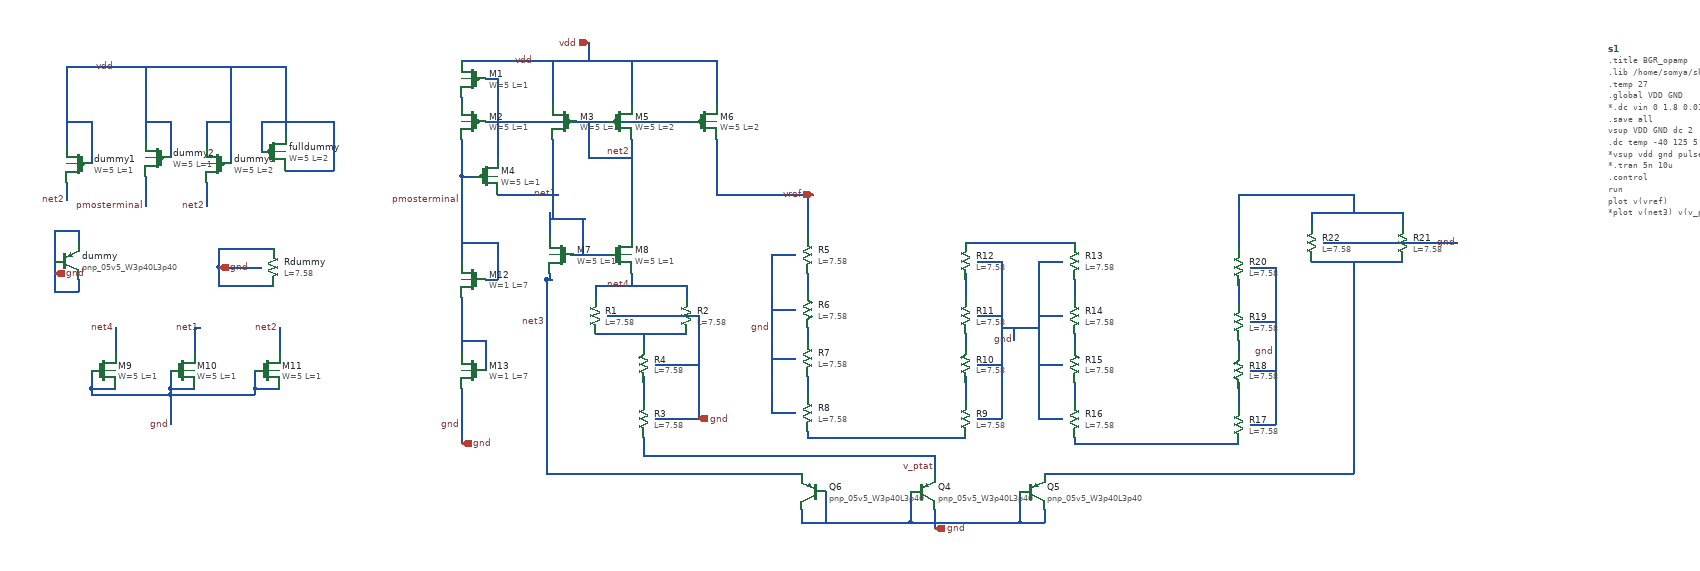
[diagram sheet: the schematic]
v {xschem version=3.4.8RC file_version=1.2}
G {}
K {}
V {}
S {}
E {}
N -70 -320 -70 -310 {lab=#net5}
N -70 -380 90 -380 {lab=vdd}
N 80 -380 80 -310 {lab=vdd}
N -10 -230 -10 -220 {lab=net2}
N 210 -380 210 -310 {lab=vdd}
N 80 -380 210 -380 {lab=vdd}
N 350 -380 350 -310 {lab=vdd}
N 200 -380 350 -380 {lab=vdd}
N -30 -280 150 -280 {lab=net2}
N 130 -280 310 -280 {lab=net2}
N -10 -160 90 -160 {lab=net1}
N -10 -280 -10 -230 {lab=net2}
N -70 -250 -70 -190 {lab=pmosterminal}
N -70 -190 -50 -190 {lab=pmosterminal}
N 140 -410 140 -380 {lab=vdd}
N -30 -350 -10 -350 {lab=net2}
N -10 -350 -10 -280 {lab=net2}
N 80 -250 80 -160 {lab=net1}
N 350 -250 350 -190 {lab=vref}
N 210 -250 210 -200 {lab=net2}
N 140 -280 140 -220 {lab=net2}
N 140 -220 210 -220 {lab=net2}
N -70 -190 -70 -120 {lab=pmosterminal}
N -720 -370 -720 -240 {lab=vdd}
N -720 -370 -560 -370 {lab=vdd}
N -490 -180 -490 -140 {lab=net2}
N -400 -280 -400 -230 {lab=vdd}
N -400 -280 -360 -280 {lab=vdd}
N -360 -200 -280 -200 {lab=vdd}
N -280 -280 -280 -200 {lab=vdd}
N -360 -280 -280 -280 {lab=vdd}
N 75 -120 135 -120 {lab=net1}
N 75 -130 75 -90 {lab=net1}
N 75 -30 75 -20 {lab=net3}
N 110 -60 170 -60 {lab=net1}
N 130 -120 130 -60 {lab=net1}
N -680 130 -680 160 {lab=gnd}
N -680 160 -640 160 {lab=gnd}
N -680 160 -680 170 {lab=gnd}
N -640 60 -640 100 {lab=net4}
N -550 130 -550 160 {lab=gnd}
N -550 160 -510 160 {lab=gnd}
N -680 170 -550 170 {lab=gnd}
N -550 160 -550 170 {lab=gnd}
N -510 60 -510 100 {lab=net1}
N -510 60 -500 60 {lab=net1}
N -370 60 -370 100 {lab=net2}
N -410 130 -410 160 {lab=gnd}
N -410 160 -370 160 {lab=gnd}
N -670 170 -410 170 {lab=gnd}
N -410 160 -410 170 {lab=gnd}
N -550 170 -550 220 {lab=gnd}
N -30 -20 -10 -20 {lab=pmosterminal}
N -70 160 -70 180 {lab=gnd}
N -70 10 -70 100 {lab=#net6}
N -70 -120 -70 -50 {lab=pmosterminal}
N -10 -80 -10 -20 {lab=pmosterminal}
N -70 -80 -10 -80 {lab=pmosterminal}
N -70 180 -70 210 {lab=gnd}
N -30 80 -30 130 {lab=#net6}
N -70 80 -30 80 {lab=#net6}
N -70 210 -70 250 {lab=gnd}
N 150 70 300 70 {lab=#net7}
N 300 -10 300 10 {lab=net4}
N 150 -10 300 -10 {lab=net4}
N 150 -10 150 10 {lab=net4}
N 230 140 230 180 {lab=#net8}
N 230 70 230 90 {lab=#net7}
N 230 240 230 270 {lab=v_ptat}
N 170 40 320 40 {lab=gnd}
N 320 40 320 210 {lab=gnd}
N 250 210 320 210 {lab=gnd}
N 250 120 320 120 {lab=gnd}
N 500 -30 500 10 {lab=#net9}
N 500 60 500 80 {lab=#net10}
N 500 140 500 180 {lab=#net11}
N 440 -60 480 -60 {lab=gnd}
N 440 -60 440 200 {lab=gnd}
N 440 200 480 200 {lab=gnd}
N 440 110 480 110 {lab=gnd}
N 440 30 480 30 {lab=gnd}
N 760 140 760 180 {lab=#net12}
N 760 70 760 90 {lab=#net13}
N 760 -30 760 10 {lab=#net14}
N 780 210 820 210 {lab=gnd}
N 820 -50 820 210 {lab=gnd}
N 780 -50 820 -50 {lab=gnd}
N 780 40 820 40 {lab=gnd}
N 780 120 820 120 {lab=gnd}
N 940 -20 940 20 {lab=#net15}
N 940 70 940 90 {lab=#net16}
N 940 150 940 190 {lab=#net17}
N 880 -50 920 -50 {lab=gnd}
N 880 -50 880 210 {lab=gnd}
N 880 210 920 210 {lab=gnd}
N 880 120 920 120 {lab=gnd}
N 880 40 920 40 {lab=gnd}
N 1210 150 1210 190 {lab=#net18}
N 1210 80 1210 100 {lab=#net19}
N 1210 -20 1210 20 {lab=#net20}
N 1230 220 1270 220 {lab=gnd}
N 1270 -40 1270 220 {lab=gnd}
N 1230 -40 1270 -40 {lab=gnd}
N 1230 50 1270 50 {lab=gnd}
N 1230 130 1270 130 {lab=gnd}
N 820 60 880 60 {lab=gnd}
N 840 60 840 80 {lab=gnd}
N 500 230 500 240 {lab=#net21}
N 500 240 760 240 {lab=#net21}
N 760 -80 940 -80 {lab=#net22}
N 940 240 940 250 {lab=#net23}
N 940 250 1210 250 {lab=#net23}
N 1480 -130 1480 -110 {lab=#net24}
N 1330 -130 1480 -130 {lab=#net24}
N 1330 -130 1330 -110 {lab=#net24}
N 1350 -80 1500 -80 {lab=gnd}
N 1330 -50 1480 -50 {lab=#net25}
N 1400 -50 1400 0 {lab=#net25}
N 1500 -80 1570 -80 {lab=gnd}
N 1210 -160 1210 -70 {lab=#net24}
N 1210 -160 1400 -160 {lab=#net24}
N 1400 -160 1400 -130 {lab=#net24}
N -470 -70 -470 -40 {lab=gnd}
N -470 -70 -380 -70 {lab=gnd}
N -470 -40 -470 -10 {lab=gnd}
N -470 -10 -380 -10 {lab=gnd}
N -470 -40 -400 -40 {lab=gnd}
N 350 -190 350 -160 {lab=vref}
N 350 -160 510 -160 {lab=vref}
N 710 360 710 390 {lab=gnd}
N 670 330 670 380 {lab=gnd}
N 670 380 710 380 {lab=gnd}
N 490 360 490 380 {lab=gnd}
N 490 380 670 380 {lab=gnd}
N 530 330 530 380 {lab=gnd}
N 850 330 850 380 {lab=gnd}
N 710 380 850 380 {lab=gnd}
N 890 360 890 380 {lab=gnd}
N 850 380 890 380 {lab=gnd}
N -700 -20 -700 0 {lab=gnd}
N -740 -50 -740 0 {lab=gnd}
N -740 0 -700 0 {lab=gnd}
N -700 -100 -700 -80 {lab=gnd}
N -740 -100 -700 -100 {lab=gnd}
N -740 -100 -740 -50 {lab=gnd}
N 500 -160 500 -90 {lab=vref}
N 230 270 710 270 {lab=v_ptat}
N 70 -20 70 0 {lab=net3}
N 70 -20 80 -20 {lab=net3}
N -680 -280 -680 -210 {lab=vdd}
N -720 -280 -680 -280 {lab=vdd}
N -590 -370 -590 -250 {lab=vdd}
N -450 -370 -450 -210 {lab=vdd}
N -490 -280 -490 -240 {lab=vdd}
N -490 -280 -450 -280 {lab=vdd}
N -550 -280 -550 -220 {lab=vdd}
N -590 -280 -550 -280 {lab=vdd}
N -720 -180 -720 -150 {lab=net2}
N -590 -190 -590 -140 {lab=pmosterminal}
N -360 -370 -360 -260 {lab=vdd}
N -590 -370 -360 -370 {lab=vdd}
N 210 -220 210 -90 {lab=net2}
N 80 -160 80 -120 {lab=net1}
N 210 -30 210 -10 {lab=net4}
N 710 270 710 300 {lab=v_ptat}
N 70 -20 70 300 {lab=net3}
N 70 300 490 300 {lab=net3}
N 1400 -40 1400 300 {lab=#net25}
N 890 300 1400 300 {lab=#net25}
C {sky130_fd_pr/pfet3_01v8.sym} -50 -350 0 1 {name=M1
W=5
L=1
body=VDD
nf=1
mult=1
ad="expr('int((@nf + 1)/2) * @W / @nf * 0.29')"
pd="expr('2*int((@nf + 1)/2) * (@W / @nf + 0.29)')"
as="expr('int((@nf + 2)/2) * @W / @nf * 0.29')"
ps="expr('2*int((@nf + 2)/2) * (@W / @nf + 0.29)')"
nrd="expr('0.29 / @W ')" nrs="expr('0.29 / @W ')"
sa=0 sb=0 sd=0
model=pfet_01v8
spiceprefix=X
}
C {sky130_fd_pr/pfet3_01v8.sym} -50 -280 0 1 {name=M2
W=5
L=1
body=VDD
nf=1
mult=1
ad="expr('int((@nf + 1)/2) * @W / @nf * 0.29')"
pd="expr('2*int((@nf + 1)/2) * (@W / @nf + 0.29)')"
as="expr('int((@nf + 2)/2) * @W / @nf * 0.29')"
ps="expr('2*int((@nf + 2)/2) * (@W / @nf + 0.29)')"
nrd="expr('0.29 / @W ')" nrs="expr('0.29 / @W ')"
sa=0 sb=0 sd=0
model=pfet_01v8
spiceprefix=X
}
C {sky130_fd_pr/pfet3_01v8.sym} 100 -280 0 1 {name=M3
W=5
L=2
body=VDD
nf=1
mult=4
ad="expr('int((@nf + 1)/2) * @W / @nf * 0.29')"
pd="expr('2*int((@nf + 1)/2) * (@W / @nf + 0.29)')"
as="expr('int((@nf + 2)/2) * @W / @nf * 0.29')"
ps="expr('2*int((@nf + 2)/2) * (@W / @nf + 0.29)')"
nrd="expr('0.29 / @W ')" nrs="expr('0.29 / @W ')"
sa=0 sb=0 sd=0
model=pfet_01v8
spiceprefix=X
}
C {sky130_fd_pr/pfet3_01v8.sym} -30 -190 0 0 {name=M4
W=5
L=1
body=VDD
nf=1
mult=2
ad="expr('int((@nf + 1)/2) * @W / @nf * 0.29')"
pd="expr('2*int((@nf + 1)/2) * (@W / @nf + 0.29)')"
as="expr('int((@nf + 2)/2) * @W / @nf * 0.29')"
ps="expr('2*int((@nf + 2)/2) * (@W / @nf + 0.29)')"
nrd="expr('0.29 / @W ')" nrs="expr('0.29 / @W ')"
sa=0 sb=0 sd=0
model=pfet_01v8
spiceprefix=X
}
C {sky130_fd_pr/pfet3_01v8.sym} 190 -280 0 0 {name=M5
W=5
L=2
body=VDD
nf=1
mult=4
ad="expr('int((@nf + 1)/2) * @W / @nf * 0.29')"
pd="expr('2*int((@nf + 1)/2) * (@W / @nf + 0.29)')"
as="expr('int((@nf + 2)/2) * @W / @nf * 0.29')"
ps="expr('2*int((@nf + 2)/2) * (@W / @nf + 0.29)')"
nrd="expr('0.29 / @W ')" nrs="expr('0.29 / @W ')"
sa=0 sb=0 sd=0
model=pfet_01v8
spiceprefix=X
}
C {sky130_fd_pr/pfet3_01v8.sym} 330 -280 0 0 {name=M6
W=5
L=2
body=VDD
nf=1
mult=4
ad="expr('int((@nf + 1)/2) * @W / @nf * 0.29')"
pd="expr('2*int((@nf + 1)/2) * (@W / @nf + 0.29)')"
as="expr('int((@nf + 2)/2) * @W / @nf * 0.29')"
ps="expr('2*int((@nf + 2)/2) * (@W / @nf + 0.29)')"
nrd="expr('0.29 / @W ')" nrs="expr('0.29 / @W ')"
sa=0 sb=0 sd=0
model=pfet_01v8
spiceprefix=X
}
C {iopin.sym} 140 -410 0 0 {name=p1 lab=vdd}
C {iopin.sym} 510 -160 0 0 {name=p5 lab=vref}
C {sky130_fd_pr/pfet3_01v8.sym} -570 -220 0 1 {name=dummy2
W=5
L=1
body=VDD
nf=1
mult=1
ad="expr('int((@nf + 1)/2) * @W / @nf * 0.29')"
pd="expr('2*int((@nf + 1)/2) * (@W / @nf + 0.29)')"
as="expr('int((@nf + 2)/2) * @W / @nf * 0.29')"
ps="expr('2*int((@nf + 2)/2) * (@W / @nf + 0.29)')"
nrd="expr('0.29 / @W ')" nrs="expr('0.29 / @W ')"
sa=0 sb=0 sd=0
model=pfet_01v8
spiceprefix=X
}
C {sky130_fd_pr/pfet3_01v8.sym} -700 -210 0 1 {name=dummy1
W=5
L=1
body=VDD
nf=1
mult=1
ad="expr('int((@nf + 1)/2) * @W / @nf * 0.29')"
pd="expr('2*int((@nf + 1)/2) * (@W / @nf + 0.29)')"
as="expr('int((@nf + 2)/2) * @W / @nf * 0.29')"
ps="expr('2*int((@nf + 2)/2) * (@W / @nf + 0.29)')"
nrd="expr('0.29 / @W ')" nrs="expr('0.29 / @W ')"
sa=0 sb=0 sd=0
model=pfet_01v8
spiceprefix=X
}
C {sky130_fd_pr/pfet3_01v8.sym} -470 -210 0 1 {name=dummy3
W=5
L=2
body=VDD
nf=1
mult=1
ad="expr('int((@nf + 1)/2) * @W / @nf * 0.29')"
pd="expr('2*int((@nf + 1)/2) * (@W / @nf + 0.29)')"
as="expr('int((@nf + 2)/2) * @W / @nf * 0.29')"
ps="expr('2*int((@nf + 2)/2) * (@W / @nf + 0.29)')"
nrd="expr('0.29 / @W ')" nrs="expr('0.29 / @W ')"
sa=0 sb=0 sd=0
model=pfet_01v8
spiceprefix=X
}
C {sky130_fd_pr/pfet3_01v8.sym} -380 -230 0 0 {name=fulldummy
W=5
L=2
body=VDD
nf=1
mult=4
ad="expr('int((@nf + 1)/2) * @W / @nf * 0.29')"
pd="expr('2*int((@nf + 1)/2) * (@W / @nf + 0.29)')"
as="expr('int((@nf + 2)/2) * @W / @nf * 0.29')"
ps="expr('2*int((@nf + 2)/2) * (@W / @nf + 0.29)')"
nrd="expr('0.29 / @W ')" nrs="expr('0.29 / @W ')"
sa=0 sb=0 sd=0
model=pfet_01v8
spiceprefix=X
}
C {sky130_fd_pr/nfet3_01v8.sym} 95 -60 0 1 {name=M7
W=5
L=1
body=GND
nf=1
mult=8
ad="expr('int((@nf + 1)/2) * @W / @nf * 0.29')"
pd="expr('2*int((@nf + 1)/2) * (@W / @nf + 0.29)')"
as="expr('int((@nf + 2)/2) * @W / @nf * 0.29')"
ps="expr('2*int((@nf + 2)/2) * (@W / @nf + 0.29)')"
nrd="expr('0.29 / @W ')" nrs="expr('0.29 / @W ')"
sa=0 sb=0 sd=0
model=nfet_01v8
spiceprefix=X
}
C {sky130_fd_pr/nfet3_01v8.sym} 190 -60 0 0 {name=M8
W=5
L=1
body=GND
nf=1
mult=8
ad="expr('int((@nf + 1)/2) * @W / @nf * 0.29')"
pd="expr('2*int((@nf + 1)/2) * (@W / @nf + 0.29)')"
as="expr('int((@nf + 2)/2) * @W / @nf * 0.29')"
ps="expr('2*int((@nf + 2)/2) * (@W / @nf + 0.29)')"
nrd="expr('0.29 / @W ')" nrs="expr('0.29 / @W ')"
sa=0 sb=0 sd=0
model=nfet_01v8
spiceprefix=X
}
C {sky130_fd_pr/nfet3_01v8.sym} -660 130 0 0 {name=M9
W=5
L=1
body=GND
nf=1
mult=4
ad="expr('int((@nf + 1)/2) * @W / @nf * 0.29')"
pd="expr('2*int((@nf + 1)/2) * (@W / @nf + 0.29)')"
as="expr('int((@nf + 2)/2) * @W / @nf * 0.29')"
ps="expr('2*int((@nf + 2)/2) * (@W / @nf + 0.29)')"
nrd="expr('0.29 / @W ')" nrs="expr('0.29 / @W ')"
sa=0 sb=0 sd=0
model=nfet_01v8
spiceprefix=X
}
C {sky130_fd_pr/nfet3_01v8.sym} -530 130 0 0 {name=M10
W=5
L=1
body=GND
nf=1
mult=6
ad="expr('int((@nf + 1)/2) * @W / @nf * 0.29')"
pd="expr('2*int((@nf + 1)/2) * (@W / @nf + 0.29)')"
as="expr('int((@nf + 2)/2) * @W / @nf * 0.29')"
ps="expr('2*int((@nf + 2)/2) * (@W / @nf + 0.29)')"
nrd="expr('0.29 / @W ')" nrs="expr('0.29 / @W ')"
sa=0 sb=0 sd=0
model=nfet_01v8
spiceprefix=X
}
C {sky130_fd_pr/nfet3_01v8.sym} -390 130 0 0 {name=M11
W=5
L=1
body=GND
nf=1
mult=2
ad="expr('int((@nf + 1)/2) * @W / @nf * 0.29')"
pd="expr('2*int((@nf + 1)/2) * (@W / @nf + 0.29)')"
as="expr('int((@nf + 2)/2) * @W / @nf * 0.29')"
ps="expr('2*int((@nf + 2)/2) * (@W / @nf + 0.29)')"
nrd="expr('0.29 / @W ')" nrs="expr('0.29 / @W ')"
sa=0 sb=0 sd=0
model=nfet_01v8
spiceprefix=X
}
C {sky130_fd_pr/nfet3_01v8.sym} -50 -20 0 1 {name=M12
W=1
L=7
body=GND
nf=1
mult=1
ad="expr('int((@nf + 1)/2) * @W / @nf * 0.29')"
pd="expr('2*int((@nf + 1)/2) * (@W / @nf + 0.29)')"
as="expr('int((@nf + 2)/2) * @W / @nf * 0.29')"
ps="expr('2*int((@nf + 2)/2) * (@W / @nf + 0.29)')"
nrd="expr('0.29 / @W ')" nrs="expr('0.29 / @W ')"
sa=0 sb=0 sd=0
model=nfet_01v8
spiceprefix=X
}
C {sky130_fd_pr/nfet3_01v8.sym} -50 130 0 1 {name=M13
W=1
L=7
body=GND
nf=1
mult=1
ad="expr('int((@nf + 1)/2) * @W / @nf * 0.29')"
pd="expr('2*int((@nf + 1)/2) * (@W / @nf + 0.29)')"
as="expr('int((@nf + 2)/2) * @W / @nf * 0.29')"
ps="expr('2*int((@nf + 2)/2) * (@W / @nf + 0.29)')"
nrd="expr('0.29 / @W ')" nrs="expr('0.29 / @W ')"
sa=0 sb=0 sd=0
model=nfet_01v8
spiceprefix=X
}
C {sky130_fd_pr/res_high_po_1p41.sym} 300 40 2 0 {name=R2
L=7.58
model=res_high_po_1p41
spiceprefix=X
mult=1}
C {sky130_fd_pr/res_high_po_1p41.sym} 150 40 2 0 {name=R1
L=7.58
model=res_high_po_1p41
spiceprefix=X
mult=1}
C {sky130_fd_pr/res_high_po_1p41.sym} 230 210 2 0 {name=R3
L=7.58
model=res_high_po_1p41
spiceprefix=X
mult=1}
C {sky130_fd_pr/res_high_po_1p41.sym} 230 120 2 0 {name=R4
L=7.58
model=res_high_po_1p41
spiceprefix=X
mult=1}
C {iopin.sym} 320 210 2 1 {name=p18 lab=gnd
}
C {sky130_fd_pr/res_high_po_1p41.sym} 500 -60 0 0 {name=R5
L=7.58
model=res_high_po_1p41
spiceprefix=X
mult=1}
C {sky130_fd_pr/res_high_po_1p41.sym} 500 30 0 0 {name=R6
L=7.58
model=res_high_po_1p41
spiceprefix=X
mult=1}
C {sky130_fd_pr/res_high_po_1p41.sym} 500 110 0 0 {name=R7
L=7.58
model=res_high_po_1p41
spiceprefix=X
mult=1}
C {sky130_fd_pr/res_high_po_1p41.sym} 500 200 0 0 {name=R8
L=7.58
model=res_high_po_1p41
spiceprefix=X
mult=1}
C {sky130_fd_pr/res_high_po_1p41.sym} 760 210 2 0 {name=R9
L=7.58
model=res_high_po_1p41
spiceprefix=X
mult=1}
C {sky130_fd_pr/res_high_po_1p41.sym} 760 120 2 0 {name=R10
L=7.58
model=res_high_po_1p41
spiceprefix=X
mult=1}
C {sky130_fd_pr/res_high_po_1p41.sym} 760 40 2 0 {name=R11
L=7.58
model=res_high_po_1p41
spiceprefix=X
mult=1}
C {sky130_fd_pr/res_high_po_1p41.sym} 760 -50 2 0 {name=R12
L=7.58
model=res_high_po_1p41
spiceprefix=X
mult=1}
C {sky130_fd_pr/res_high_po_1p41.sym} 940 -50 0 0 {name=R13
L=7.58
model=res_high_po_1p41
spiceprefix=X
mult=1}
C {sky130_fd_pr/res_high_po_1p41.sym} 940 40 0 0 {name=R14
L=7.58
model=res_high_po_1p41
spiceprefix=X
mult=1}
C {sky130_fd_pr/res_high_po_1p41.sym} 940 120 0 0 {name=R15
L=7.58
model=res_high_po_1p41
spiceprefix=X
mult=1}
C {sky130_fd_pr/res_high_po_1p41.sym} 940 210 0 0 {name=R16
L=7.58
model=res_high_po_1p41
spiceprefix=X
mult=1}
C {sky130_fd_pr/res_high_po_1p41.sym} 1210 220 2 0 {name=R17
L=7.58
model=res_high_po_1p41
spiceprefix=X
mult=1}
C {sky130_fd_pr/res_high_po_1p41.sym} 1210 130 2 0 {name=R18
L=7.58
model=res_high_po_1p41
spiceprefix=X
mult=1}
C {sky130_fd_pr/res_high_po_1p41.sym} 1210 50 2 0 {name=R19
L=7.58
model=res_high_po_1p41
spiceprefix=X
mult=1}
C {sky130_fd_pr/res_high_po_1p41.sym} 1210 -40 2 0 {name=R20
L=7.58
model=res_high_po_1p41
spiceprefix=X
mult=1}
C {sky130_fd_pr/res_high_po_1p41.sym} 1480 -80 2 0 {name=R21
L=7.58
model=res_high_po_1p41
spiceprefix=X
mult=1}
C {sky130_fd_pr/res_high_po_1p41.sym} 1330 -80 2 0 {name=R22
L=7.58
model=res_high_po_1p41
spiceprefix=X
mult=1}
C {sky130_fd_pr/res_high_po_1p41.sym} -380 -40 0 0 {name=Rdummy
L=7.58
model=res_high_po_1p41
spiceprefix=X
mult=4}
C {iopin.sym} -470 -40 0 1 {name=p25 lab=gnd
}
C {iopin.sym} -70 250 0 1 {name=p2 lab=gnd
}
C {sky130_fd_pr/pnp_05v5.sym} 690 330 0 0 {name=Q4
model=pnp_05v5_W3p40L3p40
m=8
spiceprefix=X
}
C {sky130_fd_pr/pnp_05v5.sym} 870 330 0 0 {name=Q5
model=pnp_05v5_W3p40L3p40
m=1
spiceprefix=X
}
C {sky130_fd_pr/pnp_05v5.sym} 510 330 0 1 {name=Q6
model=pnp_05v5_W3p40L3p40
m=1
spiceprefix=X
}
C {sky130_fd_pr/pnp_05v5.sym} -720 -50 0 0 {name=dummy
model=pnp_05v5_W3p40L3p40
m=18
spiceprefix=X
}
C {iopin.sym} 710 390 0 1 {name=p10 lab=gnd
}
C {iopin.sym} -740 -30 0 1 {name=p22 lab=gnd
}
C {lab_wire.sym} -500 60 0 0 {name=p8 sig_type=std_logic lab=net1}
C {lab_wire.sym} 90 -160 0 0 {name=p12 sig_type=std_logic lab=net1}
C {lab_wire.sym} -370 60 0 0 {name=p14 sig_type=std_logic lab=net2}
C {lab_wire.sym} -640 60 0 0 {name=p3 sig_type=std_logic lab=net4}
C {lab_wire.sym} 210 -10 0 0 {name=p11 sig_type=std_logic lab=net4}
C {lab_wire.sym} 70 50 0 0 {name=p9 sig_type=std_logic lab=net3}
C {lab_wire.sym} 210 -230 0 0 {name=p4 sig_type=std_logic lab=net2}
C {lab_wire.sym} -490 -140 0 0 {name=p7 sig_type=std_logic lab=net2}
C {lab_wire.sym} -720 -150 0 0 {name=p6 sig_type=std_logic lab=net2}
C {lab_wire.sym} -70 220 0 0 {name=p13 sig_type=std_logic lab=gnd}
C {lab_wire.sym} -550 220 0 0 {name=p15 sig_type=std_logic lab=gnd}
C {lab_wire.sym} -70 -150 0 0 {name=p16 sig_type=std_logic lab=pmosterminal}
C {lab_wire.sym} -590 -140 0 0 {name=p17 sig_type=std_logic lab=pmosterminal}
C {lab_wire.sym} 50 -380 0 0 {name=p23 sig_type=std_logic lab=vdd}
C {lab_wire.sym} -640 -370 0 0 {name=p26 sig_type=std_logic lab=vdd}
C {lab_wire.sym} 1270 100 0 0 {name=p21 sig_type=std_logic lab=gnd}
C {lab_wire.sym} 1570 -80 0 0 {name=p27 sig_type=std_logic lab=gnd}
C {lab_wire.sym} 840 80 0 0 {name=p20 sig_type=std_logic lab=gnd}
C {lab_wire.sym} 440 60 0 0 {name=p19 sig_type=std_logic lab=gnd}
C {code_shown.sym} 1820 -400 0 0 {name=s1 only_toplevel=false value=".title BGR_opamp
.lib /home/somya/share/pdk/sky130A/libs.tech/ngspice/sky130.lib.spice tt
.temp 27
.global VDD GND
*.dc vin 0 1.8 0.01
.save all

vsup    VDD     GND     dc      2
.dc temp -40 125 5

*vsup   vdd     gnd     pulse   0       2       10n     1u      1u      1m      100u
*.tran  5n      10u

.control
run

plot v(vref)
*plot v(net3) v(v_ptat)

 
*PLOT v(M7gate) v(ra1) v(QP2)
*plot vid1#branch vid2#branch vid3#branch vid4#branch vid5#branch
*plot i(V1) i(V2) i(V3) i(V8) i(V9)
.endc
.end
"}
C {lab_wire.sym} 710 290 0 0 {name=p24 sig_type=std_logic lab=v_ptat}
